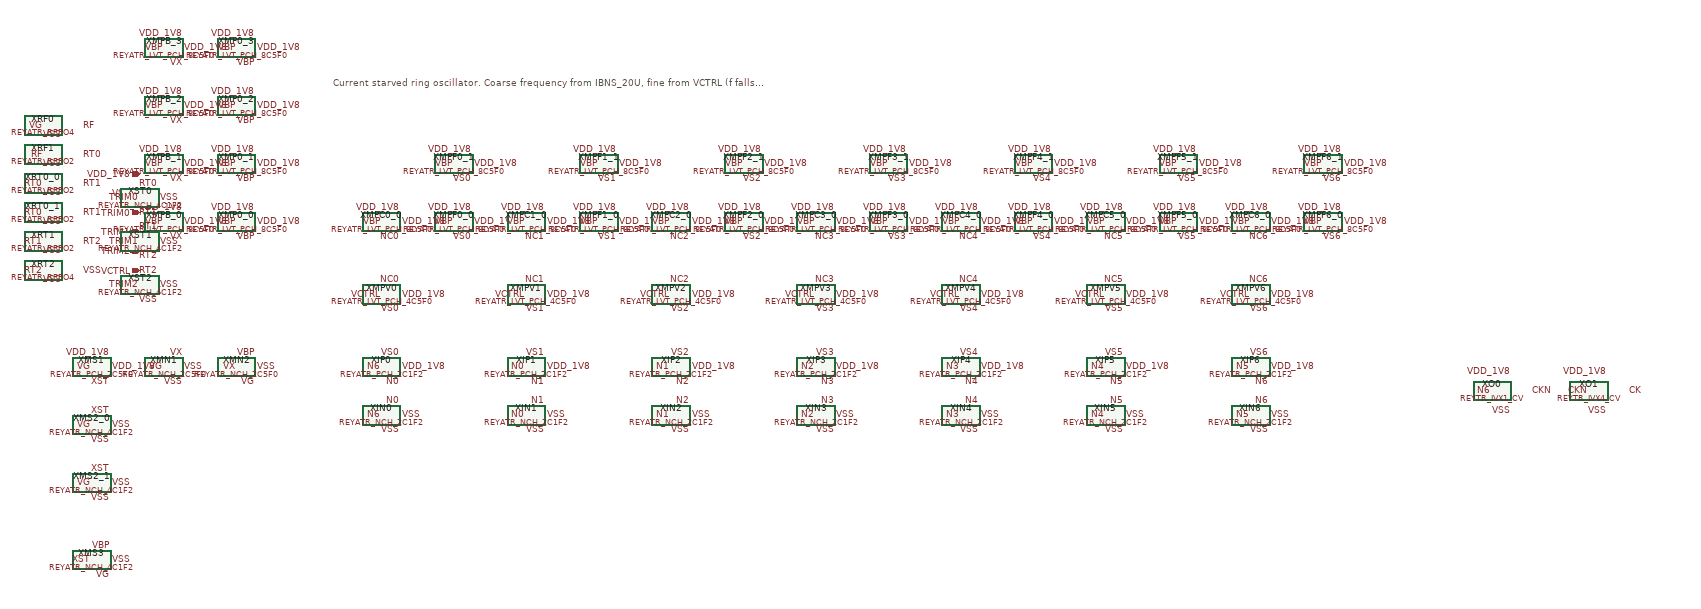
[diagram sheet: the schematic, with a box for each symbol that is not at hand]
v {xschem version=3.4.7 file_version=1.2}
G {}
K {}
V {}
S {}
E {}
T {Current starved ring oscillator. Coarse frequency from IBNS_20U, fine from VCTRL (f falls as VCTRL rises)} 0 -500 0 0 0.4 0.4 {}
C {devices/ipin.sym} -400 -300 0 0 {name=p0 lab=VDD_1V8}
C {devices/ipin.sym} -400 -260 0 0 {name=p1 lab=VSS}
C {devices/ipin.sym} -400 -220 0 0 {name=p2 lab=TRIM0}
C {devices/ipin.sym} -400 -180 0 0 {name=p3 lab=TRIM1}
C {devices/ipin.sym} -400 -140 0 0 {name=p4 lab=TRIM2}
C {devices/ipin.sym} -400 -100 0 0 {name=p5 lab=VCTRL}
C {devices/opin.sym} -400 -60 0 0 {name=p6 lab=CK}
C {REY_ATR_SKY130A/REYATR_LVT_PCH_8C5F0.sym} -200 -200 0 0 {name=XMP0_0}
C {devices/lab_pin.sym} -160 -170 1 0 {name=l1 sig_type=std_logic lab=VBP}
C {devices/lab_pin.sym} -200 -200 0 0 {name=l2 sig_type=std_logic lab=VBP}
C {devices/lab_pin.sym} -160 -230 3 0 {name=l3 sig_type=std_logic lab=VDD_1V8}
C {devices/lab_pin.sym} -160 -200 2 0 {name=l4 sig_type=std_logic lab=VDD_1V8}
C {REY_ATR_SKY130A/REYATR_LVT_PCH_8C5F0.sym} -350 -200 0 0 {name=XMPB_0}
C {devices/lab_pin.sym} -310 -170 1 0 {name=l5 sig_type=std_logic lab=VX}
C {devices/lab_pin.sym} -350 -200 0 0 {name=l6 sig_type=std_logic lab=VBP}
C {devices/lab_pin.sym} -310 -230 3 0 {name=l7 sig_type=std_logic lab=VDD_1V8}
C {devices/lab_pin.sym} -310 -200 2 0 {name=l8 sig_type=std_logic lab=VDD_1V8}
C {REY_ATR_SKY130A/REYATR_LVT_PCH_8C5F0.sym} -200 -320 0 0 {name=XMP0_1}
C {devices/lab_pin.sym} -160 -290 1 0 {name=l9 sig_type=std_logic lab=VBP}
C {devices/lab_pin.sym} -200 -320 0 0 {name=l10 sig_type=std_logic lab=VBP}
C {devices/lab_pin.sym} -160 -350 3 0 {name=l11 sig_type=std_logic lab=VDD_1V8}
C {devices/lab_pin.sym} -160 -320 2 0 {name=l12 sig_type=std_logic lab=VDD_1V8}
C {REY_ATR_SKY130A/REYATR_LVT_PCH_8C5F0.sym} -350 -320 0 0 {name=XMPB_1}
C {devices/lab_pin.sym} -310 -290 1 0 {name=l13 sig_type=std_logic lab=VX}
C {devices/lab_pin.sym} -350 -320 0 0 {name=l14 sig_type=std_logic lab=VBP}
C {devices/lab_pin.sym} -310 -350 3 0 {name=l15 sig_type=std_logic lab=VDD_1V8}
C {devices/lab_pin.sym} -310 -320 2 0 {name=l16 sig_type=std_logic lab=VDD_1V8}
C {REY_ATR_SKY130A/REYATR_LVT_PCH_8C5F0.sym} -200 -440 0 0 {name=XMP0_2}
C {devices/lab_pin.sym} -160 -410 1 0 {name=l17 sig_type=std_logic lab=VBP}
C {devices/lab_pin.sym} -200 -440 0 0 {name=l18 sig_type=std_logic lab=VBP}
C {devices/lab_pin.sym} -160 -470 3 0 {name=l19 sig_type=std_logic lab=VDD_1V8}
C {devices/lab_pin.sym} -160 -440 2 0 {name=l20 sig_type=std_logic lab=VDD_1V8}
C {REY_ATR_SKY130A/REYATR_LVT_PCH_8C5F0.sym} -350 -440 0 0 {name=XMPB_2}
C {devices/lab_pin.sym} -310 -410 1 0 {name=l21 sig_type=std_logic lab=VX}
C {devices/lab_pin.sym} -350 -440 0 0 {name=l22 sig_type=std_logic lab=VBP}
C {devices/lab_pin.sym} -310 -470 3 0 {name=l23 sig_type=std_logic lab=VDD_1V8}
C {devices/lab_pin.sym} -310 -440 2 0 {name=l24 sig_type=std_logic lab=VDD_1V8}
C {REY_ATR_SKY130A/REYATR_LVT_PCH_8C5F0.sym} -200 -560 0 0 {name=XMP0_3}
C {devices/lab_pin.sym} -160 -530 1 0 {name=l25 sig_type=std_logic lab=VBP}
C {devices/lab_pin.sym} -200 -560 0 0 {name=l26 sig_type=std_logic lab=VBP}
C {devices/lab_pin.sym} -160 -590 3 0 {name=l27 sig_type=std_logic lab=VDD_1V8}
C {devices/lab_pin.sym} -160 -560 2 0 {name=l28 sig_type=std_logic lab=VDD_1V8}
C {REY_ATR_SKY130A/REYATR_LVT_PCH_8C5F0.sym} -350 -560 0 0 {name=XMPB_3}
C {devices/lab_pin.sym} -310 -530 1 0 {name=l29 sig_type=std_logic lab=VX}
C {devices/lab_pin.sym} -350 -560 0 0 {name=l30 sig_type=std_logic lab=VBP}
C {devices/lab_pin.sym} -310 -590 3 0 {name=l31 sig_type=std_logic lab=VDD_1V8}
C {devices/lab_pin.sym} -310 -560 2 0 {name=l32 sig_type=std_logic lab=VDD_1V8}
C {REY_ATR_SKY130A/REYATR_NCH_2C5F0.sym} -350 100 0 0 {name=XMN1}
C {devices/lab_pin.sym} -310 70 3 0 {name=l33 sig_type=std_logic lab=VX}
C {devices/lab_pin.sym} -350 100 0 0 {name=l34 sig_type=std_logic lab=VG}
C {devices/lab_pin.sym} -310 130 1 0 {name=l35 sig_type=std_logic lab=VSS}
C {devices/lab_pin.sym} -310 100 2 0 {name=l36 sig_type=std_logic lab=VSS}
C {REY_ATR_SKY130A/REYATR_NCH_2C5F0.sym} -200 100 0 0 {name=XMN2}
C {devices/lab_pin.sym} -160 70 3 0 {name=l37 sig_type=std_logic lab=VBP}
C {devices/lab_pin.sym} -200 100 0 0 {name=l38 sig_type=std_logic lab=VX}
C {devices/lab_pin.sym} -160 130 1 0 {name=l39 sig_type=std_logic lab=VG}
C {devices/lab_pin.sym} -160 100 2 0 {name=l40 sig_type=std_logic lab=VSS}
C {REY_ATR_SKY130A/REYATR_PCH_2C5F0.sym} -500 100 0 0 {name=XMS1}
C {devices/lab_pin.sym} -460 130 1 0 {name=l41 sig_type=std_logic lab=XST}
C {devices/lab_pin.sym} -500 100 0 0 {name=l42 sig_type=std_logic lab=VG}
C {devices/lab_pin.sym} -460 70 3 0 {name=l43 sig_type=std_logic lab=VDD_1V8}
C {devices/lab_pin.sym} -460 100 2 0 {name=l44 sig_type=std_logic lab=VDD_1V8}
C {REY_ATR_SKY130A/REYATR_NCH_4C1F2.sym} -500 220 0 0 {name=XMS2_0}
C {devices/lab_pin.sym} -460 190 3 0 {name=l45 sig_type=std_logic lab=XST}
C {devices/lab_pin.sym} -500 220 0 0 {name=l46 sig_type=std_logic lab=VG}
C {devices/lab_pin.sym} -460 250 1 0 {name=l47 sig_type=std_logic lab=VSS}
C {devices/lab_pin.sym} -460 220 2 0 {name=l48 sig_type=std_logic lab=VSS}
C {REY_ATR_SKY130A/REYATR_NCH_4C1F2.sym} -500 340 0 0 {name=XMS2_1}
C {devices/lab_pin.sym} -460 310 3 0 {name=l49 sig_type=std_logic lab=XST}
C {devices/lab_pin.sym} -500 340 0 0 {name=l50 sig_type=std_logic lab=VG}
C {devices/lab_pin.sym} -460 370 1 0 {name=l51 sig_type=std_logic lab=VSS}
C {devices/lab_pin.sym} -460 340 2 0 {name=l52 sig_type=std_logic lab=VSS}
C {REY_ATR_SKY130A/REYATR_NCH_4C1F2.sym} -500 500 0 0 {name=XMS3}
C {devices/lab_pin.sym} -460 470 3 0 {name=l53 sig_type=std_logic lab=VBP}
C {devices/lab_pin.sym} -500 500 0 0 {name=l54 sig_type=std_logic lab=XST}
C {devices/lab_pin.sym} -460 530 1 0 {name=l55 sig_type=std_logic lab=VG}
C {devices/lab_pin.sym} -460 500 2 0 {name=l56 sig_type=std_logic lab=VSS}
C {REY_ATR_SKY130A/REYATR_RPPO4.sym} -600 -400 0 0 {name=XRF0}
C {devices/lab_pin.sym} -600 -400 0 0 {name=l57 sig_type=std_logic lab=VG}
C {devices/lab_pin.sym} -520 -400 2 0 {name=l58 sig_type=std_logic lab=RF}
C {devices/lab_pin.sym} -560 -380 1 0 {name=l59 sig_type=std_logic lab=VSS}
C {REY_ATR_SKY130A/REYATR_RPPO2.sym} -600 -340 0 0 {name=XRF1}
C {devices/lab_pin.sym} -600 -340 0 0 {name=l60 sig_type=std_logic lab=RF}
C {devices/lab_pin.sym} -520 -340 2 0 {name=l61 sig_type=std_logic lab=RT0}
C {devices/lab_pin.sym} -560 -320 1 0 {name=l62 sig_type=std_logic lab=VSS}
C {REY_ATR_SKY130A/REYATR_RPPO2.sym} -600 -280 0 0 {name=XRT0_0}
C {devices/lab_pin.sym} -600 -280 0 0 {name=l63 sig_type=std_logic lab=RT0}
C {devices/lab_pin.sym} -520 -280 2 0 {name=l64 sig_type=std_logic lab=RT1}
C {devices/lab_pin.sym} -560 -260 1 0 {name=l65 sig_type=std_logic lab=VSS}
C {REY_ATR_SKY130A/REYATR_RPPO2.sym} -600 -220 0 0 {name=XRT0_1}
C {devices/lab_pin.sym} -600 -220 0 0 {name=l66 sig_type=std_logic lab=RT0}
C {devices/lab_pin.sym} -520 -220 2 0 {name=l67 sig_type=std_logic lab=RT1}
C {devices/lab_pin.sym} -560 -200 1 0 {name=l68 sig_type=std_logic lab=VSS}
C {REY_ATR_SKY130A/REYATR_NCH_4C1F2.sym} -400 -250 0 0 {name=XST0}
C {devices/lab_pin.sym} -360 -280 3 0 {name=l69 sig_type=std_logic lab=RT0}
C {devices/lab_pin.sym} -400 -250 0 0 {name=l70 sig_type=std_logic lab=TRIM0}
C {devices/lab_pin.sym} -360 -220 1 0 {name=l71 sig_type=std_logic lab=RT1}
C {devices/lab_pin.sym} -360 -250 2 0 {name=l72 sig_type=std_logic lab=VSS}
C {REY_ATR_SKY130A/REYATR_RPPO2.sym} -600 -160 0 0 {name=XRT1}
C {devices/lab_pin.sym} -600 -160 0 0 {name=l73 sig_type=std_logic lab=RT1}
C {devices/lab_pin.sym} -520 -160 2 0 {name=l74 sig_type=std_logic lab=RT2}
C {devices/lab_pin.sym} -560 -140 1 0 {name=l75 sig_type=std_logic lab=VSS}
C {REY_ATR_SKY130A/REYATR_NCH_4C1F2.sym} -400 -160 0 0 {name=XST1}
C {devices/lab_pin.sym} -360 -190 3 0 {name=l76 sig_type=std_logic lab=RT1}
C {devices/lab_pin.sym} -400 -160 0 0 {name=l77 sig_type=std_logic lab=TRIM1}
C {devices/lab_pin.sym} -360 -130 1 0 {name=l78 sig_type=std_logic lab=RT2}
C {devices/lab_pin.sym} -360 -160 2 0 {name=l79 sig_type=std_logic lab=VSS}
C {REY_ATR_SKY130A/REYATR_RPPO4.sym} -600 -100 0 0 {name=XRT2}
C {devices/lab_pin.sym} -600 -100 0 0 {name=l80 sig_type=std_logic lab=RT2}
C {devices/lab_pin.sym} -520 -100 2 0 {name=l81 sig_type=std_logic lab=VSS}
C {devices/lab_pin.sym} -560 -80 1 0 {name=l82 sig_type=std_logic lab=VSS}
C {REY_ATR_SKY130A/REYATR_NCH_4C1F2.sym} -400 -70 0 0 {name=XST2}
C {devices/lab_pin.sym} -360 -100 3 0 {name=l83 sig_type=std_logic lab=RT2}
C {devices/lab_pin.sym} -400 -70 0 0 {name=l84 sig_type=std_logic lab=TRIM2}
C {devices/lab_pin.sym} -360 -40 1 0 {name=l85 sig_type=std_logic lab=VSS}
C {devices/lab_pin.sym} -360 -70 2 0 {name=l86 sig_type=std_logic lab=VSS}
C {REY_ATR_SKY130A/REYATR_LVT_PCH_8C5F0.sym} 250 -200 0 0 {name=XMPF0_0}
C {devices/lab_pin.sym} 290 -170 1 0 {name=l87 sig_type=std_logic lab=VS0}
C {devices/lab_pin.sym} 250 -200 0 0 {name=l88 sig_type=std_logic lab=VBP}
C {devices/lab_pin.sym} 290 -230 3 0 {name=l89 sig_type=std_logic lab=VDD_1V8}
C {devices/lab_pin.sym} 290 -200 2 0 {name=l90 sig_type=std_logic lab=VDD_1V8}
C {REY_ATR_SKY130A/REYATR_LVT_PCH_8C5F0.sym} 250 -320 0 0 {name=XMPF0_1}
C {devices/lab_pin.sym} 290 -290 1 0 {name=l91 sig_type=std_logic lab=VS0}
C {devices/lab_pin.sym} 250 -320 0 0 {name=l92 sig_type=std_logic lab=VBP}
C {devices/lab_pin.sym} 290 -350 3 0 {name=l93 sig_type=std_logic lab=VDD_1V8}
C {devices/lab_pin.sym} 290 -320 2 0 {name=l94 sig_type=std_logic lab=VDD_1V8}
C {REY_ATR_SKY130A/REYATR_LVT_PCH_8C5F0.sym} 100 -200 0 0 {name=XMPC0_0}
C {devices/lab_pin.sym} 140 -170 1 0 {name=l95 sig_type=std_logic lab=NC0}
C {devices/lab_pin.sym} 100 -200 0 0 {name=l96 sig_type=std_logic lab=VBP}
C {devices/lab_pin.sym} 140 -230 3 0 {name=l97 sig_type=std_logic lab=VDD_1V8}
C {devices/lab_pin.sym} 140 -200 2 0 {name=l98 sig_type=std_logic lab=VDD_1V8}
C {REY_ATR_SKY130A/REYATR_LVT_PCH_4C5F0.sym} 100 -50 0 0 {name=XMPV0}
C {devices/lab_pin.sym} 140 -20 1 0 {name=l99 sig_type=std_logic lab=VS0}
C {devices/lab_pin.sym} 100 -50 0 0 {name=l100 sig_type=std_logic lab=VCTRL}
C {devices/lab_pin.sym} 140 -80 3 0 {name=l101 sig_type=std_logic lab=NC0}
C {devices/lab_pin.sym} 140 -50 2 0 {name=l102 sig_type=std_logic lab=VDD_1V8}
C {REY_ATR_SKY130A/REYATR_PCH_2C1F2.sym} 100 100 0 0 {name=XIP0}
C {devices/lab_pin.sym} 140 130 1 0 {name=l103 sig_type=std_logic lab=N0}
C {devices/lab_pin.sym} 100 100 0 0 {name=l104 sig_type=std_logic lab=N6}
C {devices/lab_pin.sym} 140 70 3 0 {name=l105 sig_type=std_logic lab=VS0}
C {devices/lab_pin.sym} 140 100 2 0 {name=l106 sig_type=std_logic lab=VDD_1V8}
C {REY_ATR_SKY130A/REYATR_NCH_2C1F2.sym} 100 200 0 0 {name=XIN0}
C {devices/lab_pin.sym} 140 170 3 0 {name=l107 sig_type=std_logic lab=N0}
C {devices/lab_pin.sym} 100 200 0 0 {name=l108 sig_type=std_logic lab=N6}
C {devices/lab_pin.sym} 140 230 1 0 {name=l109 sig_type=std_logic lab=VSS}
C {devices/lab_pin.sym} 140 200 2 0 {name=l110 sig_type=std_logic lab=VSS}
C {REY_ATR_SKY130A/REYATR_LVT_PCH_8C5F0.sym} 550 -200 0 0 {name=XMPF1_0}
C {devices/lab_pin.sym} 590 -170 1 0 {name=l111 sig_type=std_logic lab=VS1}
C {devices/lab_pin.sym} 550 -200 0 0 {name=l112 sig_type=std_logic lab=VBP}
C {devices/lab_pin.sym} 590 -230 3 0 {name=l113 sig_type=std_logic lab=VDD_1V8}
C {devices/lab_pin.sym} 590 -200 2 0 {name=l114 sig_type=std_logic lab=VDD_1V8}
C {REY_ATR_SKY130A/REYATR_LVT_PCH_8C5F0.sym} 550 -320 0 0 {name=XMPF1_1}
C {devices/lab_pin.sym} 590 -290 1 0 {name=l115 sig_type=std_logic lab=VS1}
C {devices/lab_pin.sym} 550 -320 0 0 {name=l116 sig_type=std_logic lab=VBP}
C {devices/lab_pin.sym} 590 -350 3 0 {name=l117 sig_type=std_logic lab=VDD_1V8}
C {devices/lab_pin.sym} 590 -320 2 0 {name=l118 sig_type=std_logic lab=VDD_1V8}
C {REY_ATR_SKY130A/REYATR_LVT_PCH_8C5F0.sym} 400 -200 0 0 {name=XMPC1_0}
C {devices/lab_pin.sym} 440 -170 1 0 {name=l119 sig_type=std_logic lab=NC1}
C {devices/lab_pin.sym} 400 -200 0 0 {name=l120 sig_type=std_logic lab=VBP}
C {devices/lab_pin.sym} 440 -230 3 0 {name=l121 sig_type=std_logic lab=VDD_1V8}
C {devices/lab_pin.sym} 440 -200 2 0 {name=l122 sig_type=std_logic lab=VDD_1V8}
C {REY_ATR_SKY130A/REYATR_LVT_PCH_4C5F0.sym} 400 -50 0 0 {name=XMPV1}
C {devices/lab_pin.sym} 440 -20 1 0 {name=l123 sig_type=std_logic lab=VS1}
C {devices/lab_pin.sym} 400 -50 0 0 {name=l124 sig_type=std_logic lab=VCTRL}
C {devices/lab_pin.sym} 440 -80 3 0 {name=l125 sig_type=std_logic lab=NC1}
C {devices/lab_pin.sym} 440 -50 2 0 {name=l126 sig_type=std_logic lab=VDD_1V8}
C {REY_ATR_SKY130A/REYATR_PCH_2C1F2.sym} 400 100 0 0 {name=XIP1}
C {devices/lab_pin.sym} 440 130 1 0 {name=l127 sig_type=std_logic lab=N1}
C {devices/lab_pin.sym} 400 100 0 0 {name=l128 sig_type=std_logic lab=N0}
C {devices/lab_pin.sym} 440 70 3 0 {name=l129 sig_type=std_logic lab=VS1}
C {devices/lab_pin.sym} 440 100 2 0 {name=l130 sig_type=std_logic lab=VDD_1V8}
C {REY_ATR_SKY130A/REYATR_NCH_2C1F2.sym} 400 200 0 0 {name=XIN1}
C {devices/lab_pin.sym} 440 170 3 0 {name=l131 sig_type=std_logic lab=N1}
C {devices/lab_pin.sym} 400 200 0 0 {name=l132 sig_type=std_logic lab=N0}
C {devices/lab_pin.sym} 440 230 1 0 {name=l133 sig_type=std_logic lab=VSS}
C {devices/lab_pin.sym} 440 200 2 0 {name=l134 sig_type=std_logic lab=VSS}
C {REY_ATR_SKY130A/REYATR_LVT_PCH_8C5F0.sym} 850 -200 0 0 {name=XMPF2_0}
C {devices/lab_pin.sym} 890 -170 1 0 {name=l135 sig_type=std_logic lab=VS2}
C {devices/lab_pin.sym} 850 -200 0 0 {name=l136 sig_type=std_logic lab=VBP}
C {devices/lab_pin.sym} 890 -230 3 0 {name=l137 sig_type=std_logic lab=VDD_1V8}
C {devices/lab_pin.sym} 890 -200 2 0 {name=l138 sig_type=std_logic lab=VDD_1V8}
C {REY_ATR_SKY130A/REYATR_LVT_PCH_8C5F0.sym} 850 -320 0 0 {name=XMPF2_1}
C {devices/lab_pin.sym} 890 -290 1 0 {name=l139 sig_type=std_logic lab=VS2}
C {devices/lab_pin.sym} 850 -320 0 0 {name=l140 sig_type=std_logic lab=VBP}
C {devices/lab_pin.sym} 890 -350 3 0 {name=l141 sig_type=std_logic lab=VDD_1V8}
C {devices/lab_pin.sym} 890 -320 2 0 {name=l142 sig_type=std_logic lab=VDD_1V8}
C {REY_ATR_SKY130A/REYATR_LVT_PCH_8C5F0.sym} 700 -200 0 0 {name=XMPC2_0}
C {devices/lab_pin.sym} 740 -170 1 0 {name=l143 sig_type=std_logic lab=NC2}
C {devices/lab_pin.sym} 700 -200 0 0 {name=l144 sig_type=std_logic lab=VBP}
C {devices/lab_pin.sym} 740 -230 3 0 {name=l145 sig_type=std_logic lab=VDD_1V8}
C {devices/lab_pin.sym} 740 -200 2 0 {name=l146 sig_type=std_logic lab=VDD_1V8}
C {REY_ATR_SKY130A/REYATR_LVT_PCH_4C5F0.sym} 700 -50 0 0 {name=XMPV2}
C {devices/lab_pin.sym} 740 -20 1 0 {name=l147 sig_type=std_logic lab=VS2}
C {devices/lab_pin.sym} 700 -50 0 0 {name=l148 sig_type=std_logic lab=VCTRL}
C {devices/lab_pin.sym} 740 -80 3 0 {name=l149 sig_type=std_logic lab=NC2}
C {devices/lab_pin.sym} 740 -50 2 0 {name=l150 sig_type=std_logic lab=VDD_1V8}
C {REY_ATR_SKY130A/REYATR_PCH_2C1F2.sym} 700 100 0 0 {name=XIP2}
C {devices/lab_pin.sym} 740 130 1 0 {name=l151 sig_type=std_logic lab=N2}
C {devices/lab_pin.sym} 700 100 0 0 {name=l152 sig_type=std_logic lab=N1}
C {devices/lab_pin.sym} 740 70 3 0 {name=l153 sig_type=std_logic lab=VS2}
C {devices/lab_pin.sym} 740 100 2 0 {name=l154 sig_type=std_logic lab=VDD_1V8}
C {REY_ATR_SKY130A/REYATR_NCH_2C1F2.sym} 700 200 0 0 {name=XIN2}
C {devices/lab_pin.sym} 740 170 3 0 {name=l155 sig_type=std_logic lab=N2}
C {devices/lab_pin.sym} 700 200 0 0 {name=l156 sig_type=std_logic lab=N1}
C {devices/lab_pin.sym} 740 230 1 0 {name=l157 sig_type=std_logic lab=VSS}
C {devices/lab_pin.sym} 740 200 2 0 {name=l158 sig_type=std_logic lab=VSS}
C {REY_ATR_SKY130A/REYATR_LVT_PCH_8C5F0.sym} 1150 -200 0 0 {name=XMPF3_0}
C {devices/lab_pin.sym} 1190 -170 1 0 {name=l159 sig_type=std_logic lab=VS3}
C {devices/lab_pin.sym} 1150 -200 0 0 {name=l160 sig_type=std_logic lab=VBP}
C {devices/lab_pin.sym} 1190 -230 3 0 {name=l161 sig_type=std_logic lab=VDD_1V8}
C {devices/lab_pin.sym} 1190 -200 2 0 {name=l162 sig_type=std_logic lab=VDD_1V8}
C {REY_ATR_SKY130A/REYATR_LVT_PCH_8C5F0.sym} 1150 -320 0 0 {name=XMPF3_1}
C {devices/lab_pin.sym} 1190 -290 1 0 {name=l163 sig_type=std_logic lab=VS3}
C {devices/lab_pin.sym} 1150 -320 0 0 {name=l164 sig_type=std_logic lab=VBP}
C {devices/lab_pin.sym} 1190 -350 3 0 {name=l165 sig_type=std_logic lab=VDD_1V8}
C {devices/lab_pin.sym} 1190 -320 2 0 {name=l166 sig_type=std_logic lab=VDD_1V8}
C {REY_ATR_SKY130A/REYATR_LVT_PCH_8C5F0.sym} 1000 -200 0 0 {name=XMPC3_0}
C {devices/lab_pin.sym} 1040 -170 1 0 {name=l167 sig_type=std_logic lab=NC3}
C {devices/lab_pin.sym} 1000 -200 0 0 {name=l168 sig_type=std_logic lab=VBP}
C {devices/lab_pin.sym} 1040 -230 3 0 {name=l169 sig_type=std_logic lab=VDD_1V8}
C {devices/lab_pin.sym} 1040 -200 2 0 {name=l170 sig_type=std_logic lab=VDD_1V8}
C {REY_ATR_SKY130A/REYATR_LVT_PCH_4C5F0.sym} 1000 -50 0 0 {name=XMPV3}
C {devices/lab_pin.sym} 1040 -20 1 0 {name=l171 sig_type=std_logic lab=VS3}
C {devices/lab_pin.sym} 1000 -50 0 0 {name=l172 sig_type=std_logic lab=VCTRL}
C {devices/lab_pin.sym} 1040 -80 3 0 {name=l173 sig_type=std_logic lab=NC3}
C {devices/lab_pin.sym} 1040 -50 2 0 {name=l174 sig_type=std_logic lab=VDD_1V8}
C {REY_ATR_SKY130A/REYATR_PCH_2C1F2.sym} 1000 100 0 0 {name=XIP3}
C {devices/lab_pin.sym} 1040 130 1 0 {name=l175 sig_type=std_logic lab=N3}
C {devices/lab_pin.sym} 1000 100 0 0 {name=l176 sig_type=std_logic lab=N2}
C {devices/lab_pin.sym} 1040 70 3 0 {name=l177 sig_type=std_logic lab=VS3}
C {devices/lab_pin.sym} 1040 100 2 0 {name=l178 sig_type=std_logic lab=VDD_1V8}
C {REY_ATR_SKY130A/REYATR_NCH_2C1F2.sym} 1000 200 0 0 {name=XIN3}
C {devices/lab_pin.sym} 1040 170 3 0 {name=l179 sig_type=std_logic lab=N3}
C {devices/lab_pin.sym} 1000 200 0 0 {name=l180 sig_type=std_logic lab=N2}
C {devices/lab_pin.sym} 1040 230 1 0 {name=l181 sig_type=std_logic lab=VSS}
C {devices/lab_pin.sym} 1040 200 2 0 {name=l182 sig_type=std_logic lab=VSS}
C {REY_ATR_SKY130A/REYATR_LVT_PCH_8C5F0.sym} 1450 -200 0 0 {name=XMPF4_0}
C {devices/lab_pin.sym} 1490 -170 1 0 {name=l183 sig_type=std_logic lab=VS4}
C {devices/lab_pin.sym} 1450 -200 0 0 {name=l184 sig_type=std_logic lab=VBP}
C {devices/lab_pin.sym} 1490 -230 3 0 {name=l185 sig_type=std_logic lab=VDD_1V8}
C {devices/lab_pin.sym} 1490 -200 2 0 {name=l186 sig_type=std_logic lab=VDD_1V8}
C {REY_ATR_SKY130A/REYATR_LVT_PCH_8C5F0.sym} 1450 -320 0 0 {name=XMPF4_1}
C {devices/lab_pin.sym} 1490 -290 1 0 {name=l187 sig_type=std_logic lab=VS4}
C {devices/lab_pin.sym} 1450 -320 0 0 {name=l188 sig_type=std_logic lab=VBP}
C {devices/lab_pin.sym} 1490 -350 3 0 {name=l189 sig_type=std_logic lab=VDD_1V8}
C {devices/lab_pin.sym} 1490 -320 2 0 {name=l190 sig_type=std_logic lab=VDD_1V8}
C {REY_ATR_SKY130A/REYATR_LVT_PCH_8C5F0.sym} 1300 -200 0 0 {name=XMPC4_0}
C {devices/lab_pin.sym} 1340 -170 1 0 {name=l191 sig_type=std_logic lab=NC4}
C {devices/lab_pin.sym} 1300 -200 0 0 {name=l192 sig_type=std_logic lab=VBP}
C {devices/lab_pin.sym} 1340 -230 3 0 {name=l193 sig_type=std_logic lab=VDD_1V8}
C {devices/lab_pin.sym} 1340 -200 2 0 {name=l194 sig_type=std_logic lab=VDD_1V8}
C {REY_ATR_SKY130A/REYATR_LVT_PCH_4C5F0.sym} 1300 -50 0 0 {name=XMPV4}
C {devices/lab_pin.sym} 1340 -20 1 0 {name=l195 sig_type=std_logic lab=VS4}
C {devices/lab_pin.sym} 1300 -50 0 0 {name=l196 sig_type=std_logic lab=VCTRL}
C {devices/lab_pin.sym} 1340 -80 3 0 {name=l197 sig_type=std_logic lab=NC4}
C {devices/lab_pin.sym} 1340 -50 2 0 {name=l198 sig_type=std_logic lab=VDD_1V8}
C {REY_ATR_SKY130A/REYATR_PCH_2C1F2.sym} 1300 100 0 0 {name=XIP4}
C {devices/lab_pin.sym} 1340 130 1 0 {name=l199 sig_type=std_logic lab=N4}
C {devices/lab_pin.sym} 1300 100 0 0 {name=l200 sig_type=std_logic lab=N3}
C {devices/lab_pin.sym} 1340 70 3 0 {name=l201 sig_type=std_logic lab=VS4}
C {devices/lab_pin.sym} 1340 100 2 0 {name=l202 sig_type=std_logic lab=VDD_1V8}
C {REY_ATR_SKY130A/REYATR_NCH_2C1F2.sym} 1300 200 0 0 {name=XIN4}
C {devices/lab_pin.sym} 1340 170 3 0 {name=l203 sig_type=std_logic lab=N4}
C {devices/lab_pin.sym} 1300 200 0 0 {name=l204 sig_type=std_logic lab=N3}
C {devices/lab_pin.sym} 1340 230 1 0 {name=l205 sig_type=std_logic lab=VSS}
C {devices/lab_pin.sym} 1340 200 2 0 {name=l206 sig_type=std_logic lab=VSS}
C {REY_ATR_SKY130A/REYATR_LVT_PCH_8C5F0.sym} 1750 -200 0 0 {name=XMPF5_0}
C {devices/lab_pin.sym} 1790 -170 1 0 {name=l207 sig_type=std_logic lab=VS5}
C {devices/lab_pin.sym} 1750 -200 0 0 {name=l208 sig_type=std_logic lab=VBP}
C {devices/lab_pin.sym} 1790 -230 3 0 {name=l209 sig_type=std_logic lab=VDD_1V8}
C {devices/lab_pin.sym} 1790 -200 2 0 {name=l210 sig_type=std_logic lab=VDD_1V8}
C {REY_ATR_SKY130A/REYATR_LVT_PCH_8C5F0.sym} 1750 -320 0 0 {name=XMPF5_1}
C {devices/lab_pin.sym} 1790 -290 1 0 {name=l211 sig_type=std_logic lab=VS5}
C {devices/lab_pin.sym} 1750 -320 0 0 {name=l212 sig_type=std_logic lab=VBP}
C {devices/lab_pin.sym} 1790 -350 3 0 {name=l213 sig_type=std_logic lab=VDD_1V8}
C {devices/lab_pin.sym} 1790 -320 2 0 {name=l214 sig_type=std_logic lab=VDD_1V8}
C {REY_ATR_SKY130A/REYATR_LVT_PCH_8C5F0.sym} 1600 -200 0 0 {name=XMPC5_0}
C {devices/lab_pin.sym} 1640 -170 1 0 {name=l215 sig_type=std_logic lab=NC5}
C {devices/lab_pin.sym} 1600 -200 0 0 {name=l216 sig_type=std_logic lab=VBP}
C {devices/lab_pin.sym} 1640 -230 3 0 {name=l217 sig_type=std_logic lab=VDD_1V8}
C {devices/lab_pin.sym} 1640 -200 2 0 {name=l218 sig_type=std_logic lab=VDD_1V8}
C {REY_ATR_SKY130A/REYATR_LVT_PCH_4C5F0.sym} 1600 -50 0 0 {name=XMPV5}
C {devices/lab_pin.sym} 1640 -20 1 0 {name=l219 sig_type=std_logic lab=VS5}
C {devices/lab_pin.sym} 1600 -50 0 0 {name=l220 sig_type=std_logic lab=VCTRL}
C {devices/lab_pin.sym} 1640 -80 3 0 {name=l221 sig_type=std_logic lab=NC5}
C {devices/lab_pin.sym} 1640 -50 2 0 {name=l222 sig_type=std_logic lab=VDD_1V8}
C {REY_ATR_SKY130A/REYATR_PCH_2C1F2.sym} 1600 100 0 0 {name=XIP5}
C {devices/lab_pin.sym} 1640 130 1 0 {name=l223 sig_type=std_logic lab=N5}
C {devices/lab_pin.sym} 1600 100 0 0 {name=l224 sig_type=std_logic lab=N4}
C {devices/lab_pin.sym} 1640 70 3 0 {name=l225 sig_type=std_logic lab=VS5}
C {devices/lab_pin.sym} 1640 100 2 0 {name=l226 sig_type=std_logic lab=VDD_1V8}
C {REY_ATR_SKY130A/REYATR_NCH_2C1F2.sym} 1600 200 0 0 {name=XIN5}
C {devices/lab_pin.sym} 1640 170 3 0 {name=l227 sig_type=std_logic lab=N5}
C {devices/lab_pin.sym} 1600 200 0 0 {name=l228 sig_type=std_logic lab=N4}
C {devices/lab_pin.sym} 1640 230 1 0 {name=l229 sig_type=std_logic lab=VSS}
C {devices/lab_pin.sym} 1640 200 2 0 {name=l230 sig_type=std_logic lab=VSS}
C {REY_ATR_SKY130A/REYATR_LVT_PCH_8C5F0.sym} 2050 -200 0 0 {name=XMPF6_0}
C {devices/lab_pin.sym} 2090 -170 1 0 {name=l231 sig_type=std_logic lab=VS6}
C {devices/lab_pin.sym} 2050 -200 0 0 {name=l232 sig_type=std_logic lab=VBP}
C {devices/lab_pin.sym} 2090 -230 3 0 {name=l233 sig_type=std_logic lab=VDD_1V8}
C {devices/lab_pin.sym} 2090 -200 2 0 {name=l234 sig_type=std_logic lab=VDD_1V8}
C {REY_ATR_SKY130A/REYATR_LVT_PCH_8C5F0.sym} 2050 -320 0 0 {name=XMPF6_1}
C {devices/lab_pin.sym} 2090 -290 1 0 {name=l235 sig_type=std_logic lab=VS6}
C {devices/lab_pin.sym} 2050 -320 0 0 {name=l236 sig_type=std_logic lab=VBP}
C {devices/lab_pin.sym} 2090 -350 3 0 {name=l237 sig_type=std_logic lab=VDD_1V8}
C {devices/lab_pin.sym} 2090 -320 2 0 {name=l238 sig_type=std_logic lab=VDD_1V8}
C {REY_ATR_SKY130A/REYATR_LVT_PCH_8C5F0.sym} 1900 -200 0 0 {name=XMPC6_0}
C {devices/lab_pin.sym} 1940 -170 1 0 {name=l239 sig_type=std_logic lab=NC6}
C {devices/lab_pin.sym} 1900 -200 0 0 {name=l240 sig_type=std_logic lab=VBP}
C {devices/lab_pin.sym} 1940 -230 3 0 {name=l241 sig_type=std_logic lab=VDD_1V8}
C {devices/lab_pin.sym} 1940 -200 2 0 {name=l242 sig_type=std_logic lab=VDD_1V8}
C {REY_ATR_SKY130A/REYATR_LVT_PCH_4C5F0.sym} 1900 -50 0 0 {name=XMPV6}
C {devices/lab_pin.sym} 1940 -20 1 0 {name=l243 sig_type=std_logic lab=VS6}
C {devices/lab_pin.sym} 1900 -50 0 0 {name=l244 sig_type=std_logic lab=VCTRL}
C {devices/lab_pin.sym} 1940 -80 3 0 {name=l245 sig_type=std_logic lab=NC6}
C {devices/lab_pin.sym} 1940 -50 2 0 {name=l246 sig_type=std_logic lab=VDD_1V8}
C {REY_ATR_SKY130A/REYATR_PCH_2C1F2.sym} 1900 100 0 0 {name=XIP6}
C {devices/lab_pin.sym} 1940 130 1 0 {name=l247 sig_type=std_logic lab=N6}
C {devices/lab_pin.sym} 1900 100 0 0 {name=l248 sig_type=std_logic lab=N5}
C {devices/lab_pin.sym} 1940 70 3 0 {name=l249 sig_type=std_logic lab=VS6}
C {devices/lab_pin.sym} 1940 100 2 0 {name=l250 sig_type=std_logic lab=VDD_1V8}
C {REY_ATR_SKY130A/REYATR_NCH_2C1F2.sym} 1900 200 0 0 {name=XIN6}
C {devices/lab_pin.sym} 1940 170 3 0 {name=l251 sig_type=std_logic lab=N6}
C {devices/lab_pin.sym} 1900 200 0 0 {name=l252 sig_type=std_logic lab=N5}
C {devices/lab_pin.sym} 1940 230 1 0 {name=l253 sig_type=std_logic lab=VSS}
C {devices/lab_pin.sym} 1940 200 2 0 {name=l254 sig_type=std_logic lab=VSS}
C {REY_TR_SKY130A/REYTR_IVX1_CV.sym} 2400 150 0 0 {name=XO0}
C {devices/lab_pin.sym} 2400 150 0 0 {name=l255 sig_type=std_logic lab=N6}
C {devices/lab_pin.sym} 2480 150 2 0 {name=l256 sig_type=std_logic lab=CKN}
C {devices/lab_pin.sym} 2440 110 3 0 {name=l257 sig_type=std_logic lab=VDD_1V8}
C {devices/lab_pin.sym} 2440 190 1 0 {name=l258 sig_type=std_logic lab=VSS}
C {REY_TR_SKY130A/REYTR_IVX4_CV.sym} 2600 150 0 0 {name=XO1}
C {devices/lab_pin.sym} 2600 150 0 0 {name=l259 sig_type=std_logic lab=CKN}
C {devices/lab_pin.sym} 2680 150 2 0 {name=l260 sig_type=std_logic lab=CK}
C {devices/lab_pin.sym} 2640 110 3 0 {name=l261 sig_type=std_logic lab=VDD_1V8}
C {devices/lab_pin.sym} 2640 190 1 0 {name=l262 sig_type=std_logic lab=VSS}
